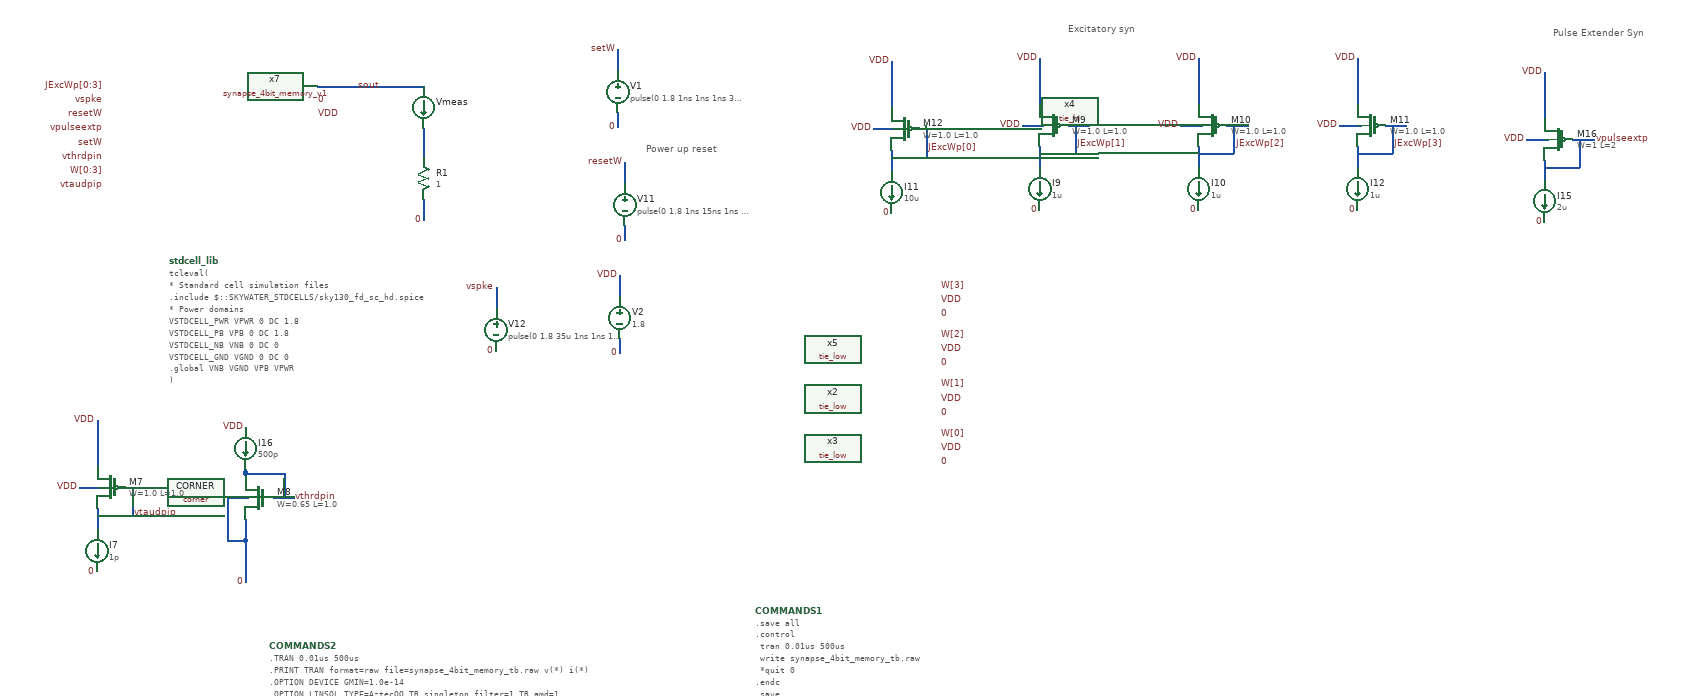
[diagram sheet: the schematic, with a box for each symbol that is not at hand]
v {xschem version=3.4.5 file_version=1.2
}
G {}
K {}
V {}
S {}
E {}
B 2 1720 -630 2520 -230 {flags=graph
y1=0
y2=2
ypos1=0
ypos2=2
divy=5
subdivy=1
unity=1
x1=0
x2=0.0005
divx=5
subdivx=1
xlabmag=1.0
ylabmag=1.0
node="x7.x2.net1
x7.net1[0]
x7.net1[1]
x7.net1[2]
x7.net1[3]
x7.spke
vspke
x7.x1.net1"
color="18 6 7 8 4 10 15 8"
dataset=-1
unitx=1
logx=0
logy=0
hilight_wave=3}
B 2 110 -1420 910 -1020 {flags=graph
y1=0
y2=2
ypos1=0
ypos2=2
divy=5
subdivy=1
unity=1
x1=0
x2=0.0005
divx=5
subdivx=1
xlabmag=1.0
ylabmag=1.0
node="x7.spke
vspke
x7.x1.net1"
color="6 5 8"
dataset=-1
unitx=1
logx=0
logy=0
hilight_wave=-1}
B 2 942.5 -1420 1742.5 -1020 {flags=graph
y1=-0.11
y2=1.9
ypos1=0
ypos2=2
divy=5
subdivy=1
unity=1
x1=0
x2=0.0005
divx=5
subdivx=1
xlabmag=1.0
ylabmag=1.0
node="x7.x1.net1
vpulseextp"
color="8 4"
dataset=-1
unitx=1
logx=0
logy=0
}
B 2 1780 -1420 2580 -1020 {flags=graph
y1=0
y2=2
ypos1=0
ypos2=2
divy=5
subdivy=1
unity=1
x1=0
x2=0.0005
divx=5
subdivx=1
xlabmag=1.0
ylabmag=1.0
node="x7.x2.vsin
setw
resetw
x7.spke"
color="4 5 6 20"
dataset=-1
unitx=1
logx=0
logy=0
hilight_wave=1}
T {Power up reset} 1055 -845 0 0 0.4 0.4 {}
T {Excitatory syn} 1652.5 -1015 0 0 0.4 0.4 {}
T {Pulse Extender Syn} 2340 -1010 0 0 0.4 0.4 {}
N 842.5 -637.5 842.5 -607.5 {
lab=vspke}
N 1025 -725 1025 -705 {
lab=0}
N 1025 -815 1025 -785 {
lab=resetW}
N 1017.5 -565 1017.5 -545 {
lab=0}
N 1017.5 -655 1017.5 -625 {
lab=VDD}
N 590 -922.5 740 -922.5 {
lab=sout}
N 740 -862.5 740 -822.5 {
lab=#net1}
N 1015 -885 1015 -865 {
lab=0}
N 1015 -975 1015 -945 {
lab=setW}
N 740 -762.5 740 -742.5 {
lab=0}
N 740 -742.5 740 -732.5 {
lab=0}
N 1377.5 -862.5 1407.5 -862.5 {
lab=VDD}
N 1402.5 -832.5 1402.5 -827.5 {
lab=JExcWp[0]}
N 1402.5 -827.5 1402.5 -807.5 {
lab=JExcWp[0]}
N 1442.5 -862.5 1472.5 -862.5 {
lab=JExcWp[0]}
N 1402.5 -957.5 1402.5 -897.5 {
lab=VDD}
N 1402.5 -822.5 1452.5 -822.5 {
lab=JExcWp[0]}
N 1452.5 -862.5 1452.5 -822.5 {
lab=JExcWp[0]}
N 1402.5 -807.5 1402.5 -802.5 {
lab=JExcWp[0]}
N 1402.5 -897.5 1402.5 -892.5 {
lab=VDD}
N 1587.5 -867.5 1617.5 -867.5 {
lab=VDD}
N 1612.5 -837.5 1612.5 -832.5 {
lab=JExcWp[1]}
N 1612.5 -832.5 1612.5 -812.5 {
lab=JExcWp[1]}
N 1652.5 -867.5 1682.5 -867.5 {
lab=JExcWp[1]}
N 1612.5 -962.5 1612.5 -902.5 {
lab=VDD}
N 1612.5 -827.5 1662.5 -827.5 {
lab=JExcWp[1]}
N 1662.5 -867.5 1662.5 -827.5 {
lab=JExcWp[1]}
N 1612.5 -812.5 1612.5 -807.5 {
lab=JExcWp[1]}
N 1612.5 -902.5 1612.5 -897.5 {
lab=VDD}
N 1812.5 -867.5 1842.5 -867.5 {
lab=VDD}
N 1837.5 -837.5 1837.5 -832.5 {
lab=JExcWp[2]}
N 1837.5 -832.5 1837.5 -812.5 {
lab=JExcWp[2]}
N 1877.5 -867.5 1907.5 -867.5 {
lab=JExcWp[2]}
N 1837.5 -962.5 1837.5 -902.5 {
lab=VDD}
N 1837.5 -827.5 1887.5 -827.5 {
lab=JExcWp[2]}
N 1887.5 -867.5 1887.5 -827.5 {
lab=JExcWp[2]}
N 1837.5 -812.5 1837.5 -807.5 {
lab=JExcWp[2]}
N 1837.5 -902.5 1837.5 -897.5 {
lab=VDD}
N 2037.5 -867.5 2067.5 -867.5 {
lab=VDD}
N 2062.5 -837.5 2062.5 -832.5 {
lab=JExcWp[3]}
N 2062.5 -832.5 2062.5 -812.5 {
lab=JExcWp[3]}
N 2102.5 -867.5 2132.5 -867.5 {
lab=JExcWp[3]}
N 2062.5 -962.5 2062.5 -902.5 {
lab=VDD}
N 2062.5 -827.5 2112.5 -827.5 {
lab=JExcWp[3]}
N 2112.5 -867.5 2112.5 -827.5 {
lab=JExcWp[3]}
N 2062.5 -812.5 2062.5 -807.5 {
lab=JExcWp[3]}
N 2062.5 -902.5 2062.5 -897.5 {
lab=VDD}
N 2302.5 -847.5 2332.5 -847.5 {
lab=VDD}
N 2327.5 -817.5 2327.5 -812.5 {
lab=vpulseextp}
N 2327.5 -812.5 2327.5 -792.5 {
lab=vpulseextp}
N 2367.5 -847.5 2397.5 -847.5 {
lab=vpulseextp}
N 2327.5 -942.5 2327.5 -882.5 {
lab=VDD}
N 2327.5 -807.5 2377.5 -807.5 {
lab=vpulseextp}
N 2377.5 -847.5 2377.5 -807.5 {
lab=vpulseextp}
N 2327.5 -792.5 2327.5 -787.5 {
lab=vpulseextp}
N 2327.5 -882.5 2327.5 -877.5 {
lab=VDD}
N 252.5 -355 282.5 -355 {
lab=VDD}
N 277.5 -325 277.5 -320 {
lab=vtaudpip}
N 277.5 -320 277.5 -300 {
lab=vtaudpip}
N 317.5 -355 347.5 -355 {
lab=vtaudpip}
N 277.5 -450 277.5 -390 {
lab=VDD}
N 277.5 -315 327.5 -315 {
lab=vtaudpip}
N 327.5 -355 327.5 -315 {
lab=vtaudpip}
N 277.5 -300 277.5 -295 {
lab=vtaudpip}
N 277.5 -390 277.5 -385 {
lab=VDD}
N 462.5 -340 492.5 -340 {
lab=0}
N 487.5 -310 487.5 -305 {
lab=0}
N 487.5 -305 487.5 -285 {
lab=0}
N 527.5 -340 557.5 -340 {
lab=vthrdpin}
N 487.5 -285 487.5 -280 {
lab=0}
N 487.5 -375 487.5 -370 {
lab=vthrdpin}
N 487.5 -380 487.5 -375 {
lab=vthrdpin}
N 487.5 -280 487.5 -220 {
lab=0}
N 462.5 -340 462.5 -280 {
lab=0}
N 462.5 -280 487.5 -280 {
lab=0}
N 487.5 -375 542.5 -375 {
lab=vthrdpin}
N 542.5 -375 542.5 -340 {
lab=vthrdpin}
C {devices/code.sym} 380 -675 0 0 {name=stdcell_lib only_toplevel=true value="tcleval(
* Standard cell simulation files
.include $::SKYWATER_STDCELLS/sky130_fd_sc_hd.spice

* Power domains
VSTDCELL_PWR VPWR 0 DC 1.8
VSTDCELL_PB  VPB  0 DC 1.8
VSTDCELL_NB  VNB  0 DC 0
VSTDCELL_GND VGND 0 DC 0
.global VNB VGND VPB VPWR
)"}
C {sky130_fd_pr/corner.sym} 230 -675 0 0 {name=CORNER only_toplevel=true corner=tt}
C {devices/lab_pin.sym} 327.5 -317.5 0 1 {name=p16 sig_type=std_logic lab=vtaudpip}
C {devices/lab_pin.sym} 555 -340 0 1 {name=p26 sig_type=std_logic lab=vthrdpin}
C {devices/vsource.sym} 842.5 -577.5 0 1 {name=V12 value="pulse(0 1.8 35u 1ns 1ns 1ns 10us)"}
C {devices/lab_pin.sym} 842.5 -637.5 0 0 {name=p19 sig_type=std_logic lab=vspke}
C {devices/lab_pin.sym} 287.5 -902.5 0 0 {name=p1 sig_type=std_logic lab=vspke}
C {devices/lab_pin.sym} 287.5 -782.5 0 0 {name=p2 sig_type=std_logic lab=vtaudpip
}
C {devices/lab_pin.sym} 287.5 -822.5 0 0 {name=p4 sig_type=std_logic lab=vthrdpin
}
C {devices/lab_pin.sym} 287.5 -862.5 0 0 {name=p7 sig_type=std_logic lab=vpulseextp}
C {devices/lab_pin.sym} 1025 -815 0 0 {name=p51 sig_type=std_logic lab=resetW}
C {devices/vsource.sym} 1025 -755 0 0 {name=V11 value="pulse(0 1.8 1ns 15ns 1ns 29us 10ms 1)"}
C {devices/lab_pin.sym} 287.5 -882.5 0 0 {name=p3 sig_type=std_logic lab=resetW}
C {devices/lab_pin.sym} 1470 -500 2 0 {name=p9 sig_type=std_logic lab=W[1]}
C {devices/lab_pin.sym} 287.5 -802.5 0 0 {name=p10 sig_type=std_logic lab=W[0:3]
}
C {devices/vsource.sym} 1017.5 -595 0 0 {name=V2 value=1.8}
C {devices/lab_pin.sym} 1017.5 -655 0 0 {name=p35 sig_type=std_logic lab=VDD}
C {devices/lab_pin.sym} 587.5 -902.5 2 0 {name=p11 sig_type=std_logic lab=0}
C {devices/lab_pin.sym} 587.5 -882.5 2 0 {name=p12 sig_type=std_logic lab=VDD}
C {devices/res.sym} 740 -792.5 0 0 {name=R1
value=1
footprint=1206
device=resistor
m=1}
C {devices/lab_pin.sym} 680 -922.5 1 0 {name=p13 sig_type=std_logic lab=sout}
C {devices/ammeter.sym} 740 -892.5 0 0 {name=Vmeas savecurrent=true}
C {devices/lab_pin.sym} 1470 -430 2 0 {name=p14 sig_type=std_logic lab=W[0]}
C {devices/lab_pin.sym} 1470 -460 2 0 {name=p6 sig_type=std_logic lab=0}
C {devices/lab_pin.sym} 1470 -390 2 0 {name=p15 sig_type=std_logic lab=0
}
C {devices/lab_pin.sym} 1470 -480 2 0 {name=p17 sig_type=std_logic lab=VDD}
C {devices/lab_pin.sym} 1470 -410 2 0 {name=p18 sig_type=std_logic lab=VDD}
C {devices/lab_pin.sym} 1015 -975 0 0 {name=p20 sig_type=std_logic lab=setW}
C {devices/vsource.sym} 1015 -915 0 0 {name=V1 value="pulse(0 1.8 1ns 1ns 1ns 3us 12us 2)"}
C {devices/lab_pin.sym} 287.5 -842.5 0 0 {name=p8 sig_type=std_logic lab=setW}
C {tie_low.sym} 1320 -410 0 0 {name=x3}
C {tie_low.sym} 1320 -480 0 0 {name=x2}
C {devices/lab_pin.sym} 1025 -705 0 0 {name=p81 sig_type=std_logic lab=0}
C {devices/lab_pin.sym} 842.5 -547.5 0 0 {name=p21 sig_type=std_logic lab=0}
C {devices/lab_pin.sym} 1015 -865 0 0 {name=p22 sig_type=std_logic lab=0}
C {devices/lab_pin.sym} 740 -732.5 0 0 {name=p23 sig_type=std_logic lab=0}
C {devices/lab_pin.sym} 1017.5 -545 0 0 {name=p25 sig_type=std_logic lab=0}
C {devices/simulator_commands_shown.sym} 521.25 -130 0 0 {name=COMMANDS2
simulator=Xyce
only_toplevel=false 
value="
.TRAN 0.01us 500us
.PRINT TRAN format=raw file=synapse_4bit_memory_tb.raw v(*) i(*)
.OPTION DEVICE GMIN=1.0e-14
.OPTION LINSOL TYPE=AztecOO TR_singleton_filter=1 TR_amd=1
"}
C {devices/simulator_commands_shown.sym} 1210 -180 0 0 {name=COMMANDS1
simulator=ngspice
only_toplevel=false 
value="
.save all
.control
  tran 0.01us 500us
  write synapse_4bit_memory_tb.raw
  *quit 0
.endc
.save
"}
C {tie_hi.sym} 1320 -620 0 0 {name=x4}
C {tie_low.sym} 1320 -550 0 0 {name=x5}
C {devices/lab_pin.sym} 1470 -640 2 0 {name=p27 sig_type=std_logic lab=W[3]}
C {devices/lab_pin.sym} 1470 -570 2 0 {name=p28 sig_type=std_logic lab=W[2]}
C {devices/lab_pin.sym} 1470 -600 2 0 {name=p29 sig_type=std_logic lab=0}
C {devices/lab_pin.sym} 1470 -530 2 0 {name=p30 sig_type=std_logic lab=0}
C {devices/lab_pin.sym} 1470 -620 2 0 {name=p31 sig_type=std_logic lab=VDD}
C {devices/lab_pin.sym} 1470 -550 2 0 {name=p32 sig_type=std_logic lab=VDD}
C {synapse_4bit_memory_v1.sym} 437.5 -852.5 0 0 {name=x7}
C {devices/lab_pin.sym} 1452.5 -835 0 1 {name=p54 sig_type=std_logic lab=JExcWp[0]}
C {sky130_fd_pr/pfet_01v8.sym} 1422.5 -862.5 0 1 {name=M12
L=1.0
W=1.0
nf=1
mult=1
ad="'int((nf+1)/2) * W/nf * 0.29'" 
pd="'2*int((nf+1)/2) * (W/nf + 0.29)'"
as="'int((nf+2)/2) * W/nf * 0.29'" 
ps="'2*int((nf+2)/2) * (W/nf + 0.29)'"
nrd="'0.29 / W'" nrs="'0.29 / W'"
sa=0 sb=0 sd=0
model=pfet_01v8
spiceprefix=X
}
C {devices/lab_pin.sym} 1402.5 -742.5 0 0 {name=p105 sig_type=std_logic lab=0}
C {devices/lab_pin.sym} 1377.5 -862.5 0 0 {name=p106 sig_type=std_logic lab=VDD}
C {devices/isource.sym} 1402.5 -772.5 0 0 {name=I11 value=10u}
C {devices/lab_pin.sym} 1402.5 -957.5 0 0 {name=p114 sig_type=std_logic lab=VDD}
C {devices/lab_pin.sym} 1662.5 -840 0 1 {name=p107 sig_type=std_logic lab=JExcWp[1]}
C {sky130_fd_pr/pfet_01v8.sym} 1632.5 -867.5 0 1 {name=M9
L=1.0
W=1.0
nf=1
mult=1
ad="'int((nf+1)/2) * W/nf * 0.29'" 
pd="'2*int((nf+1)/2) * (W/nf + 0.29)'"
as="'int((nf+2)/2) * W/nf * 0.29'" 
ps="'2*int((nf+2)/2) * (W/nf + 0.29)'"
nrd="'0.29 / W'" nrs="'0.29 / W'"
sa=0 sb=0 sd=0
model=pfet_01v8
spiceprefix=X
}
C {devices/lab_pin.sym} 1612.5 -747.5 0 0 {name=p113 sig_type=std_logic lab=0}
C {devices/lab_pin.sym} 1587.5 -867.5 0 0 {name=p110 sig_type=std_logic lab=VDD}
C {devices/isource.sym} 1612.5 -777.5 0 0 {name=I9 value=1u}
C {devices/lab_pin.sym} 1612.5 -962.5 0 0 {name=p116 sig_type=std_logic lab=VDD}
C {devices/lab_pin.sym} 1887.5 -840 0 1 {name=p118 sig_type=std_logic lab=JExcWp[2]}
C {sky130_fd_pr/pfet_01v8.sym} 1857.5 -867.5 0 1 {name=M10
L=1.0
W=1.0
nf=1
mult=1
ad="'int((nf+1)/2) * W/nf * 0.29'" 
pd="'2*int((nf+1)/2) * (W/nf + 0.29)'"
as="'int((nf+2)/2) * W/nf * 0.29'" 
ps="'2*int((nf+2)/2) * (W/nf + 0.29)'"
nrd="'0.29 / W'" nrs="'0.29 / W'"
sa=0 sb=0 sd=0
model=pfet_01v8
spiceprefix=X
}
C {devices/lab_pin.sym} 1837.5 -747.5 0 0 {name=p120 sig_type=std_logic lab=0}
C {devices/lab_pin.sym} 1812.5 -867.5 0 0 {name=p122 sig_type=std_logic lab=VDD}
C {devices/isource.sym} 1837.5 -777.5 0 0 {name=I10 value=1u}
C {devices/lab_pin.sym} 1837.5 -962.5 0 0 {name=p123 sig_type=std_logic lab=VDD}
C {devices/lab_pin.sym} 2112.5 -840 0 1 {name=p124 sig_type=std_logic lab=JExcWp[3]}
C {sky130_fd_pr/pfet_01v8.sym} 2082.5 -867.5 0 1 {name=M11
L=1.0
W=1.0
nf=1
mult=1
ad="'int((nf+1)/2) * W/nf * 0.29'" 
pd="'2*int((nf+1)/2) * (W/nf + 0.29)'"
as="'int((nf+2)/2) * W/nf * 0.29'" 
ps="'2*int((nf+2)/2) * (W/nf + 0.29)'"
nrd="'0.29 / W'" nrs="'0.29 / W'"
sa=0 sb=0 sd=0
model=pfet_01v8
spiceprefix=X
}
C {devices/lab_pin.sym} 2062.5 -747.5 0 0 {name=p125 sig_type=std_logic lab=0}
C {devices/lab_pin.sym} 2037.5 -867.5 0 0 {name=p126 sig_type=std_logic lab=VDD}
C {devices/isource.sym} 2062.5 -777.5 0 0 {name=I12 value=1u}
C {devices/lab_pin.sym} 2062.5 -962.5 0 0 {name=p127 sig_type=std_logic lab=VDD}
C {devices/lab_pin.sym} 287.5 -922.5 0 0 {name=p5 sig_type=std_logic lab=JExcWp[0:3]}
C {sky130_fd_pr/pfet_01v8.sym} 2347.5 -847.5 0 1 {name=M16
L=2
W=1
nf=1
mult=1
ad="'int((nf+1)/2) * W/nf * 0.29'" 
pd="'2*int((nf+1)/2) * (W/nf + 0.29)'"
as="'int((nf+2)/2) * W/nf * 0.29'" 
ps="'2*int((nf+2)/2) * (W/nf + 0.29)'"
nrd="'0.29 / W'" nrs="'0.29 / W'"
sa=0 sb=0 sd=0
model=pfet_01v8
spiceprefix=X
}
C {devices/lab_pin.sym} 2327.5 -730 0 0 {name=p128 sig_type=std_logic lab=0}
C {devices/lab_pin.sym} 2302.5 -847.5 0 0 {name=p155 sig_type=std_logic lab=VDD}
C {devices/isource.sym} 2327.5 -760 0 0 {name=I15 value=2u}
C {devices/lab_pin.sym} 2327.5 -942.5 0 0 {name=p156 sig_type=std_logic lab=VDD}
C {devices/lab_pin.sym} 2397.5 -847.5 2 0 {name=p157 sig_type=std_logic lab=vpulseextp}
C {sky130_fd_pr/pfet_01v8.sym} 297.5 -355 0 1 {name=M7
L=1.0
W=1.0
nf=1
mult=1
ad="'int((nf+1)/2) * W/nf * 0.29'" 
pd="'2*int((nf+1)/2) * (W/nf + 0.29)'"
as="'int((nf+2)/2) * W/nf * 0.29'" 
ps="'2*int((nf+2)/2) * (W/nf + 0.29)'"
nrd="'0.29 / W'" nrs="'0.29 / W'"
sa=0 sb=0 sd=0
model=pfet_01v8
spiceprefix=X
}
C {devices/lab_pin.sym} 277.5 -235 0 0 {name=p44 sig_type=std_logic lab=0}
C {devices/lab_pin.sym} 252.5 -355 0 0 {name=p47 sig_type=std_logic lab=VDD}
C {devices/isource.sym} 277.5 -265 0 0 {name=I7 value=1p}
C {devices/lab_pin.sym} 277.5 -450 0 0 {name=p69 sig_type=std_logic lab=VDD}
C {devices/lab_pin.sym} 487.5 -220 0 0 {name=p84 sig_type=std_logic lab=0}
C {devices/isource.sym} 487.5 -410 0 0 {name=I16 value=500p}
C {sky130_fd_pr/nfet_01v8.sym} 507.5 -340 0 1 {name=M8
L=1.0
W=0.65
nf=1 
mult=1
ad="'int((nf+1)/2) * W/nf * 0.29'" 
pd="'2*int((nf+1)/2) * (W/nf + 0.29)'"
as="'int((nf+2)/2) * W/nf * 0.29'" 
ps="'2*int((nf+2)/2) * (W/nf + 0.29)'"
nrd="'0.29 / W'" nrs="'0.29 / W'"
sa=0 sb=0 sd=0
model=nfet_01v8
spiceprefix=X
}
C {devices/lab_pin.sym} 487.5 -440 0 0 {name=p40 sig_type=std_logic lab=VDD}
